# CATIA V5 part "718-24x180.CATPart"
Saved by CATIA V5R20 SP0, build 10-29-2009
Part number: 718-24x180
Definition: NONE
Nomenclature: 718-24x180
Source: Unknown
Description: 718-24x180
Bounding box of the stored display mesh (mm): x 0 to 210, y -16 to 16, z -16 to 16
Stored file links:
  C:\Users\Utente\Desktop\IO LAVORO\3D X SITO CF\X SITO\718\718-24x180.CATPart

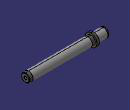
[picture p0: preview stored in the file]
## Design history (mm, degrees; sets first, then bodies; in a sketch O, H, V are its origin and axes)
Body1 "718-24x180" (main body)
  Solid1: solid without history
